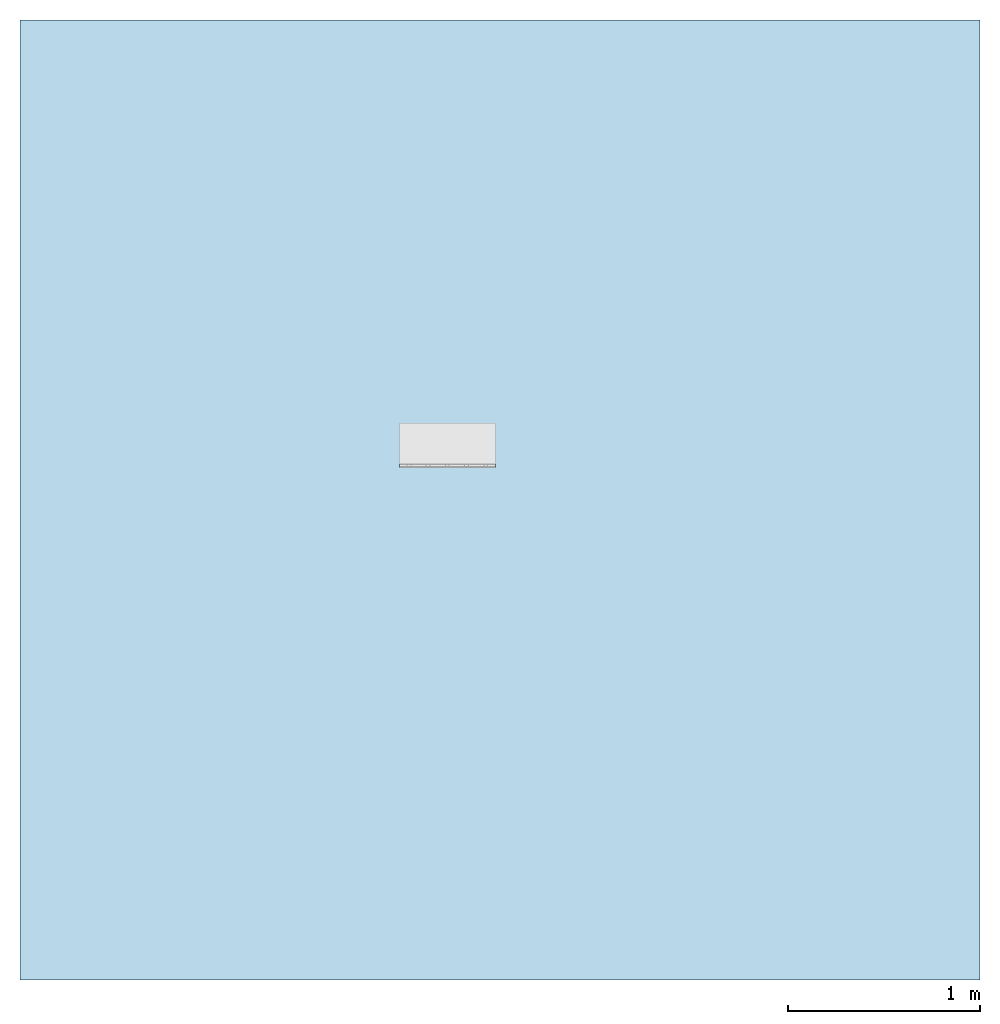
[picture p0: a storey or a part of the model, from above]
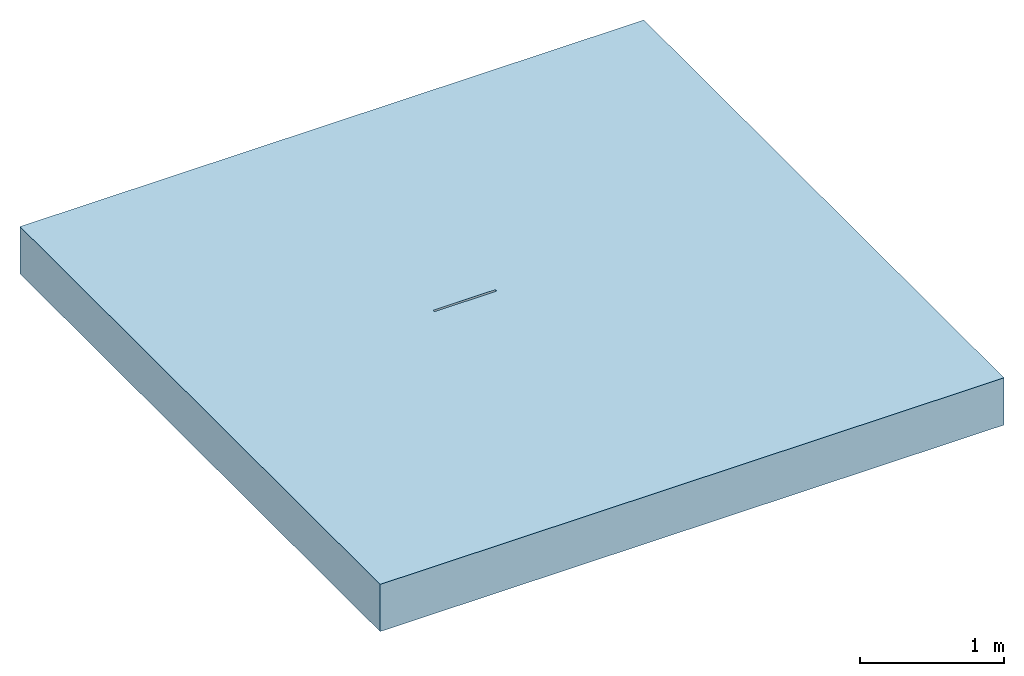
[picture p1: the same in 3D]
Properties of the parts of a building model (IFC2X3)

# File
Description: ViewDefinition [CoordinationView]
File name: 24213 - No 0.1J Constant Depth Channel - 500mm LG - Invert Depth 240mm.ifc
Time: 2013-10-30T14:06:07
Written by: Autodesk Revit 2013
Made in: 20120221_2030(x64)

# IfcProject, Project Number
LongName: Project Name; Phase: Project Status

# IfcSite, Default
RefLatitude: 42, 21, 30, 344238; RefLongitude: -71, -3, -35, -194702; RefElevation: 0 mm

# IfcBuilding
Pset_BuildingCommon - NumberOfStoreys: 1
Other - Client Name: Owner; Project Name: Project Name; Project Status: Project Status; Project Address: ## Street City, State Zip; Project Number: Project Number; Project Issue Date: Issue Date

# IfcBuildingStorey, Level 1
LongName: Level 1; Elevation: 0 mm
Constraints - Elevation Base: 0; Elevation: 0 mm
Graphics - Color: 0; Symbol at End 2 Default: yes; Symbol at End 1 Default: no; Symbol: M_Level Head - Circle: M_Level Head - Circle; Line Weight: 1; Line Pattern: Center
Dimensions - Computation Height: 0 mm
Identity Data - Name: Level 1; Building Story: yes; Structural: no

# IfcBuildingElementProxy: 24213 - No 0.1J Constant Depth Channel - 500mm LG - Invert Depth 240mm, Civil-Drainage-Channel-ACO-MultiDrain-M200DS-Brickslot-Channel-System:24213 - No 0.1J Constant Depth Channel - 500mm LG - Invert Depth 240mm:24213 - No 0.1J Constant Depth Channel - 500mm LG - Invert Depth 240mm:196059
In: Level 1
Material: Stainless Steel (F), Vienite® Synthetic Resin Concrete
Constraints - Level: Level: Level 1; Moves With Nearby Elements: no
Phasing - Phase Created: New Construction
Dimensions - Brickslot Grating Void Depth: 0 mm; FloorCut_Length: -500 mm; Brickslot Void Length: -500 mm; Brickslot Access Unit Void Bottom Depth: 6105 mm; Volume: 8783836 mm3; Brickslot Access Unit Void Depth: 6000 mm; Custom_Void_Length: 0 mm; EndCap Position: 500 mm; Length: 1000 mm; FloorCut_Width: 235 mm; Length Drain: -500 mm; EndCap_Height: 265 mm; FloorCut_Depth: 265 mm; FloorCut_HorPosition: 117.5 mm; InvDepth: 140 mm; Depth: 265 mm
Construction - 408998_Load Class C250 & D400_Brickslot Grating_Stainless Steel_1000mm Long: no; 23219 - Universal Endcap (Female End): no; 408999_Load Class C250 & D400_Brickslot Grating_Stainless Steel_500mm Long: yes; 409000_Load Class C250 & D400_Brickslot_Access Unit_Stainless Steel_500mm Long: no; 23219 - Universal Endcap (Male End): no; 23410_Sump Unit: no; Constant Depth Channel_1000: no; Constant Depth Channel_500: yes; Shallow Depth Channel: no; Shallow Depth Channel with seal: no
Pset_BuildingElementProxyCommon - Reference: 24213 - No 0.1J Constant Depth Channel - 500mm LG - Invert Depth 240mm
Model Properties - End Cap Product code 23219: No 306 Universal End Cap - 235mm wide x 365mm long - Spigot Ø160mm x 75mm long - Silver - Polypropylene - 0.4kg; Brickslot Grating Product code 408998: N/A; Brickslot Grating Product code 408999: Load Class C250/D400 - Brickslot Stainless Steel - 500mm long x 105mm high - 10mm Slot - Intake area 10000mm²/m - 4.8kg; Brickslot Access Unit Product code 409000: Load Class C250/D400 - Brickslot Access Unit Stainless Steel - 500mm long x 105mm high - 10mm Slot - Intake area 10000mm²/m - 8.5 Kg
Green Building Properties - Edge Rail Recycled Material Content: Between 40% - 90%; Channel Recyclable: Fully recyclable; Edge Rail Recyclable: Fully recyclable; Channel Recycled Material Content: 20% minimum
General - SerialNumber: 0; TagNumber: 0
Identity Data - Installation guidelines: http://www.aco.co.uk/download.php?id=173; Fax: +44 (0)1462 815895; Telephone: +44 (0)1462 816666; Watermark 1: This file is the property of ACO Technologies PLC; Model: ACO MultiDrain MDS Brickslot - M200DS; Watermarked With: BIM Manager Premium Suite; Address: ACO Business Park, Hitchin Road, Shefford, Bedfordshire, United Kingdom SG17 5TE; URL: www.aco.co.uk; Product Page URL: http://www.aco.co.uk/product_detail.php?id=58; Assembly Code: D2040; Cost: 0; Product Code: 24213; Manufacturer: ACO Technologies plc - ACO Water Management Division; Type Comments: ACO MultiDrain M200DS 0.1J Constant Depth Channel 500mm Long; e-mail Technical: technical@aco.co.uk; Price: POA - contact ACO; e-mail Sales: customersupport@aco.co.uk; Product brochure: http://www.aco.co.uk/download.php?id=173; OmniClass Title: Rainwater Removal; Maintenance guidelines: http://www.aco.co.uk/download.php?id=173; Watermark 2: This file is water marked and users are prohibited to reproduce, adapt, distribute this information; Model Description: Channel drainage system; Watermarked By: www.aco.co.uk; OmniClass Number: 23.70.50.24; Assembly Description: Rain Water Drainage
Data - Invert Depth: 240mm; Concrete Surround Volume - Load Class A 15 - Concrete Pavement: 0.11m³/m; Concrete Surround Volume - Load Class D 400 - Concrete Pavement: 0.24m³/m; ACO Hydraulic Design Software: http://www.acodesign.co.uk; Product Standard: BS EN 1433:2002, CE marked; Installation - Concrete Grade: Refer to brochure; Hydraulic Performance: http://www.aco.co.uk/download.php?id=173; Concrete Surround Volume - Load Class B 125 - C 250 - Concrete Pavement: 0.17m³/m; Product Weight: 18.9 Kg; Channel C.S.A: 0.035m²; Load Class: A 15 - D 400; Product Dimensions: 500mm x 235mm x 265mm (LxWxH)
Other - Revision: 1; CreatedBy: www.aco.co.uk
Materials and Finishes - Channel Colour: Brown; Edge Rail Colour: Self; Channel Material: Vienite® Synthetic Resin Concrete; Edge Rail Material: Stainless Steel Grade 304

# IfcOpeningElement: Recess (2)
In: Level 1
Constraints - Height Offset From Level: 0 mm; Related to Mass: no; Room Bounding: yes; Level: Level: Level 1
Phasing - Phase Created: New Construction
Structural - Structural: no; Enable Analytical Model: no
Dimensions - Perimeter: 20000 mm; Volume: 9967917500 mm3; Area: 25000000 mm2; Thickness: 400 mm
Analytical Properties - Absorptance: 0.1; Roughness: 1; Heat Transfer Coefficient (U): 2.0925; Thermal Resistance (R): 0.477897; Thermal mass: 543920
Construction - Function: 0; Default Thickness: 400 mm
Graphics - Coarse Scale Fill Color: 0
Materials and Finishes - Structural Material: Earth

# IfcSlab: Floor:Generic Floor - 400mm, Floor:Generic Floor - 400mm:193825
In: Level 1
PredefinedType: FLOOR; Material: Earth 400 mm
Constraints - Height Offset From Level: 0 mm; Related to Mass: no; Room Bounding: yes; Level: Level: Level 1
Phasing - Phase Created: New Construction
Structural - Structural: no; Enable Analytical Model: no
Dimensions - Perimeter: 20000 mm; Volume: 9967917500 mm3; Area: 25000000 mm2; Thickness: 400 mm
Pset_SlabCommon - Reference: Generic Floor - 400mm; IsExternal: no; LoadBearing: yes
Analytical Properties - Absorptance: 0.1; Roughness: 1; Heat Transfer Coefficient (U): 2.0925; Thermal Resistance (R): 0.477897; Thermal mass: 543920
Construction - Function: 0; Default Thickness: 400 mm
Graphics - Coarse Scale Fill Color: 0
Materials and Finishes - Structural Material: Earth
